VERSION 5.7 ;
  NOWIREEXTENSIONATPIN ON ;
  DIVIDERCHAR "/" ;
  BUSBITCHARS "[]" ;
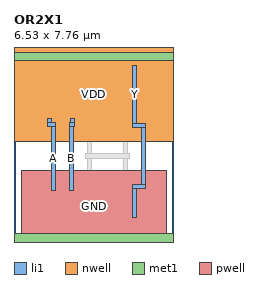
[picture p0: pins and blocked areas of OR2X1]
MACRO OR2X1
  CLASS CORE ;
  FOREIGN OR2X1 ;
  ORIGIN 0.000 0.000 ;
  SIZE 6.530 BY 7.760 ;
  SYMMETRY X Y ;
  SITE unitrh ;
  PIN Y
    DIRECTION OUTPUT ;
    USE SIGNAL ;
    ANTENNADIFFAREA 0.771900 ;
    PORT
      LAYER li1 ;
        RECT 4.850 4.845 5.020 7.200 ;
        RECT 4.850 4.675 5.385 4.845 ;
        RECT 5.215 2.345 5.385 4.675 ;
        RECT 4.845 2.175 5.385 2.345 ;
        RECT 4.845 1.020 5.015 2.175 ;
    END
  END Y
  PIN A
    DIRECTION INPUT ;
    USE SIGNAL ;
    ANTENNAGATEAREA 1.027250 ;
    PORT
      LAYER li1 ;
        RECT 1.360 4.890 1.530 5.050 ;
        RECT 1.360 4.720 1.685 4.890 ;
        RECT 1.515 2.095 1.685 4.720 ;
    END
  END A
  PIN B
    DIRECTION INPUT ;
    USE SIGNAL ;
    ANTENNAGATEAREA 1.026450 ;
    PORT
      LAYER li1 ;
        RECT 2.290 4.890 2.460 5.050 ;
        RECT 2.255 4.720 2.460 4.890 ;
        RECT 2.255 2.095 2.425 4.720 ;
    END
  END B
  PIN VDD
    DIRECTION INOUT ;
    USE POWER ;
    SHAPE ABUTMENT ;
    PORT
      LAYER nwell ;
        RECT 0.000 4.110 6.530 7.940 ;
      LAYER met1 ;
        RECT 0.000 7.410 6.530 7.760 ;
    END
  END VDD
  PIN GND
    DIRECTION INOUT ;
    USE GROUND ;
    SHAPE ABUTMENT ;
    PORT
      LAYER pwell ;
        RECT 0.320 0.000 6.210 2.900 ;
      LAYER met1 ;
        RECT 0.000 0.000 6.530 0.350 ;
    END
  END GND
  OBS
      LAYER li1 ;
        RECT 0.000 7.410 6.530 7.760 ;
        RECT 0.320 4.290 0.660 7.410 ;
        RECT 1.195 5.475 1.365 7.205 ;
        RECT 1.635 5.735 1.805 7.410 ;
        RECT 2.075 7.005 3.125 7.175 ;
        RECT 2.075 5.475 2.245 7.005 ;
        RECT 1.195 5.305 2.245 5.475 ;
        RECT 2.515 5.475 2.685 6.745 ;
        RECT 2.955 5.735 3.125 7.005 ;
        RECT 2.515 5.305 3.165 5.475 ;
        RECT 0.320 0.350 0.660 2.900 ;
        RECT 1.100 0.795 1.270 1.925 ;
        RECT 2.995 1.920 3.165 5.305 ;
        RECT 3.650 4.290 3.990 7.410 ;
        RECT 4.410 5.365 4.580 7.410 ;
        RECT 5.290 5.365 5.460 7.410 ;
        RECT 1.585 1.750 3.165 1.920 ;
        RECT 1.585 1.015 1.755 1.750 ;
        RECT 2.070 0.795 2.240 1.570 ;
        RECT 2.555 1.015 2.725 1.750 ;
        RECT 3.040 0.795 3.210 1.570 ;
        RECT 1.100 0.625 3.210 0.795 ;
        RECT 1.100 0.350 1.270 0.625 ;
        RECT 1.585 0.350 1.755 0.625 ;
        RECT 2.070 0.350 2.240 0.625 ;
        RECT 2.555 0.350 2.725 0.625 ;
        RECT 3.040 0.350 3.210 0.625 ;
        RECT 3.650 0.350 3.990 2.900 ;
        RECT 4.475 2.100 4.645 5.045 ;
        RECT 5.870 4.290 6.210 7.410 ;
        RECT 4.365 0.800 4.535 1.930 ;
        RECT 5.335 0.800 5.505 1.930 ;
        RECT 4.365 0.630 5.505 0.800 ;
        RECT 4.365 0.350 4.535 0.630 ;
        RECT 4.850 0.350 5.020 0.630 ;
        RECT 5.335 0.350 5.505 0.630 ;
        RECT 5.870 0.350 6.210 2.900 ;
        RECT 0.000 0.000 6.530 0.350 ;
      LAYER mcon ;
        RECT 0.775 7.495 0.945 7.665 ;
        RECT 1.145 7.495 1.315 7.665 ;
        RECT 1.515 7.495 1.685 7.665 ;
        RECT 1.885 7.495 2.055 7.665 ;
        RECT 2.255 7.495 2.425 7.665 ;
        RECT 2.625 7.495 2.795 7.665 ;
        RECT 2.995 7.495 3.165 7.665 ;
        RECT 3.365 7.495 3.535 7.665 ;
        RECT 4.105 7.495 4.275 7.665 ;
        RECT 4.475 7.495 4.645 7.665 ;
        RECT 4.845 7.495 5.015 7.665 ;
        RECT 5.215 7.495 5.385 7.665 ;
        RECT 5.585 7.495 5.755 7.665 ;
        RECT 2.995 3.425 3.165 3.595 ;
        RECT 4.475 3.425 4.645 3.595 ;
        RECT 0.775 0.095 0.945 0.265 ;
        RECT 1.145 0.095 1.315 0.265 ;
        RECT 1.515 0.095 1.685 0.265 ;
        RECT 1.885 0.095 2.055 0.265 ;
        RECT 2.255 0.095 2.425 0.265 ;
        RECT 2.625 0.095 2.795 0.265 ;
        RECT 2.995 0.095 3.165 0.265 ;
        RECT 3.365 0.095 3.535 0.265 ;
        RECT 4.105 0.095 4.275 0.265 ;
        RECT 4.475 0.095 4.645 0.265 ;
        RECT 4.845 0.095 5.015 0.265 ;
        RECT 5.215 0.095 5.385 0.265 ;
        RECT 5.585 0.095 5.755 0.265 ;
      LAYER met1 ;
        RECT 2.965 3.595 3.195 3.625 ;
        RECT 4.445 3.595 4.675 3.625 ;
        RECT 2.935 3.425 4.705 3.595 ;
        RECT 2.965 3.395 3.195 3.425 ;
        RECT 4.445 3.395 4.675 3.425 ;
  END
END OR2X1
END LIBRARY

